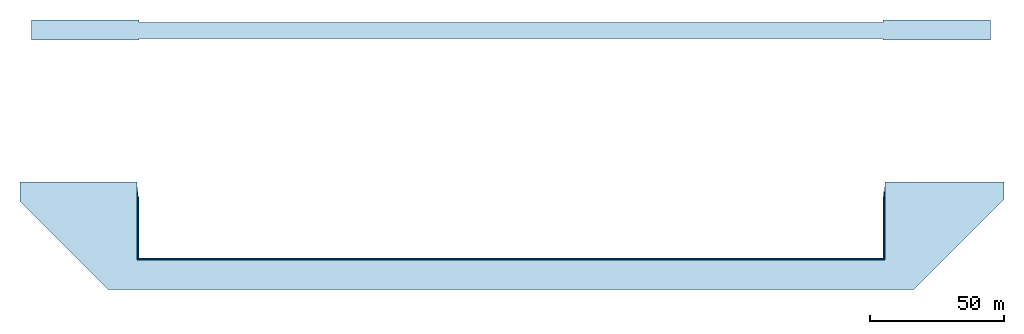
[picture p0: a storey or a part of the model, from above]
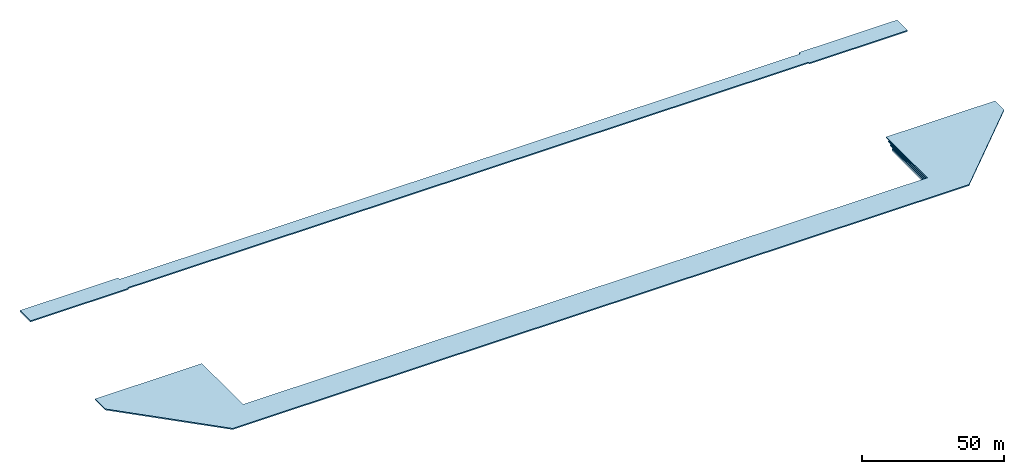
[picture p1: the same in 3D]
Properties of the parts of a building model (IFC2X3)

# File
Description: ViewDefinition [CoordinationView_V2.0]
Time: 2021-10-13T23:05:21
Written by: The EXPRESS Data Manager Version 5.02.0100.07 : 28 Aug 2013
Made in: 20210420_1515(x64) - Exporter 20.2.40.65 - 代替 UI 20.2.40.65
Comment: STEP Physical File produced by: The EXPRESS Data Manager Version 5.02.0100.07 : 28 Aug 2013 * Module: EDMstepFileFactory/EDMstandAlone * Creation date: Wed Oct 13 23:05:21 2021 * Host: A7687-TADA8 * Database: C:\Users\a9056\AppData\Local\Temp\cd053f27-3a5d-4f9c-bb79-c97ac7f12df1\53492a80-ce37-4b92-be3e-2d8bfc265d27\ifc * Database version: 5507 * Database creation date: Wed Oct 13 23:05:14 2021 * Schema: IFC2X3 * Model: DataRepository.ifc * Model creation date: Wed Oct 13 23:05:15 2021 * Header model: DataRepository.ifc_HeaderModel * Header model creation date: Wed Oct 13 23:05:15 2021 * EDMuser: sdai-user * EDMgroup: sdai-group * License ID and type: 5605 : Permanent license. Expiry date: * EDMstepFileFactory options: 020000

# IfcSite, Default
RefLatitude: 35, 53, 9, 550781; RefLongitude: 140, 22, 58, 619384; RefElevation: 0 mm

# IfcBuilding
Pset_BuildingCommon - NumberOfStoreys: 3

# IfcBuildingStorey: レベル:レベル 上表示 (3)
Name | LongName | Elevation (mm)
矢板 | 矢板 | 0
AP+8.200 | AP+8.200 | 8200
AP+10.800 | AP+10.800 | 10800

# IfcBuildingElementProxy: 鋼矢板10H型 (796)
In: 矢板
Type - Pset_BuildingElementProxyCommon - Reference: 鋼矢板10H型
Type - Pset_QuantityTakeOff - Reference: 鋼矢板10H型
Pset_BuildingElementProxyCommon - sets with these values: 2
Name (鋼矢板10H型:鋼矢板10H型:...)
734945
735249
735363
735376
735379
735382
735385
735388
735391
735394
735397
735400
735403
735406
735409
735412
735415
735418
735421
735424
735427
735430
735433
735436
735439
735442
735445
735448
735451
735454
735457
735460
735463
735466
735469
735472
735475
735478
735481
735484
735487
735490
735493
735496
735499
735502
735505
735508
735511
735514
735517
735520
735523
735526
735529
735532
735535
735538
735541
735544
735547
735550
735553
735556
735559
735562
735565
735568
735571
735574
735577
735580
735583
735586
735589
735592
735595
735598
735601
735604
735607
735610
735613
735616
735619
735622
735625
735628
735631
735634
735637
736566
736910
736923
736926
736929
736932
736935
736938
736941
736944
736947
736950
736953
736956
736959
736962
736965
736968
736971
736974
736977
736980
736983
736986
736989
736992
736995
736998
737001
737004
737007
737010
737013
737016
737019
737022
737025
737028
737031
737034
737037
737040
737043
737046
737049
737052
737055
737058
737061
737064
737067
737070
737073
737076
737079
737082
737085
737088
737091
737094
737097
737100
737103
737106
737109
737112
737115
737118
737121
737124
737127
737130
737133
737136
737139
737142
737145
737148
737151
737154
737157
737160
737163
737166
737169
737172
737175
737178
737181
737184
737187
737190
737193
737196
737199
737202
737205
737208
737211
737214
737217
737220
737223
737226
737229
737232
737235
737238
737241
737244
737247
737250
737253
737256
737259
737262
737265
737268
737271
737274
737277
737280
737283
737286
737289
737292
737295
737298
737301
737304
737307
737310
737313
737316
737319
737322
737325
737328
737331
737334
737337
737340
737343
737346
737349
737352
737355
737358
737361
737364
737367
737370
737373
737376
737379
737382
737385
737388
737391
737394
737397
737400
737403
737406
737409
737412
737415
737418
737421
737424
737427
737430
737433
737436
737439
737442
737445
737448
737451
737454
737457
737460
737463
737466
737469
737472
737475
737478
737481
737484
737487
737490
737493
737496
737499
737502
737505
737508
737511
737514
737517
737530
737533
737536
737539
737542
737545
737548
737551
737554
737557
737560
737563
737566
737569
737572
737575
737578
737581
737584
737587
737590
737593
737596
737599
737602
737605
737608
737611
737614
737617
737620
737623
737626
737629
737632
737635
737638
737641
737644
737647
737650
737653
737656
737659
737662
737665
737668
737671
737674
737677
737680
737683
737686
737689
737692
737695
737698
737701
737704
737707
737710
737713
737716
737719
737722
737725
737728
737731
737734
737737
737740
737743
737746
737749
737752
737755
737758
737761
737764
737767
737770
737773
737776
737779
737782
737785
737788
737791
737794
737797
737800
737803
737806
737809
737812
737815
737818
737821
737824
737827
737830
737833
737836
737839
737842
737899
737978
738010
738055
738068
738071
738074
738077
738080
738083
738086
738089
738092
738095
738098
738101
738104
738107
738110
738113
738116
738119
738122
738125
738128
738131
738134
738137
738140
738143
738146
738149
738152
738155
738158
738161
738164
738167
738170
738173
738176
738179
738182
738185
738188
738191
738194
738197
738200
738203
738206
738209
738212
738215
738218
738221
738224
738227
738230
738233
738236
738239
738242
738245
738248
738251
738254
738257
738260
738263
738266
738269
738272
738275
738278
738281
738284
738287
738290
738293
738296
738299
738302
738305
738308
738311
738314
738317
738320
738323
738326
738329
738342
738353
738356
738359
738362
738365
738368
738371
738374
738377
738380
738383
738386
738389
738392
738395
738398
738401
738404
738407
738410
738413
738416
738419
738422
738425
738428
738431
738434
738437
738440
738443
738446
738449
738452
738455
738458
738461
738464
738467
738470
738473
738476
738479
738482
738485
738488
738491
738494
738497
738500
738503
738506
738509
738512
738515
738518
738521
738524
738527
738530
738533
738536
738539
738542
738545
738548
738551
738554
738557
738560
738563
738566
738569
738572
738575
738578
738581
738584
738587
738590
738593
738596
738599
738602
738605
738608
738611
738614
738617
738620
738623
738626
738629
738632
738635
738638
738641
738644
738647
738650
738653
738656
738659
738662
738665
738668
738671
738674
738677
738680
738683
738686
738689
738692
738695
738698
738701
738704
738707
738710
738713
738716
738719
738722
738725
738728
738731
738734
738737
738740
738743
738746
738749
738752
738755
738758
738761
738764
738767
738770
738773
738776
738779
738782
738785
738788
738791
738794
738797
738800
738803
738806
738809
738812
738815
738818
738821
738824
738827
738830
738833
738836
738839
738842
738845
738848
738851
738854
738857
738860
738863
738866
738869
738872
738875
738878
738881
738884
738887
738890
738893
738896
738899
738902
738905
738908
738911
738914
738917
738920
738923
738926
738929
738932
738935
738938
738941
738944
738947
738958
738961
738964
738967
738970
738973
738976
738979
738982
738985
738988
738991
738994
738997
739000
739003
739006
739009
739012
739015
739018
739021
739024
739027
739030
739033
739036
739039
739042
739045
739048
739051
739054
739057
739060
739063
739066
739069
739072
739075
739078
739081
739084
739087
739090
739093
739096
739099
739102
739105
739108
739111
739114
739117
739120
739123
739126
739129
739132
739135
739138
739141
739144
739147
739150
739153
739156
739159
739162
739165
739168
739171
739174
739177
739180
739183
739186
739189
739192
739195
739198
739201
739204
739207
739210
739213
739216
739219
739222
739225
739228
739231
739234
739237
739240
739243
739246
739249
739252
739255
739258
739261
739264
739267
739270
739273
739276

# IfcSlab: かごマット, かごマット:かごマット:775933
In: AP+8.200
Type - PredefinedType: FLOOR
Type - Pset_QuantityTakeOff - Reference: かごマット
Type - Pset_ReinforcementBarPitchOfSlab - Reference: かごマット
Type - Pset_SlabCommon - IsExternal: no; Reference: かごマット
Pset_QuantityTakeOff - sets with these values: 2
Pset_SlabCommon - PitchAngle: 0 deg

# IfcSlab: アスファルト, アスファルト:アスファルト:769145
In: AP+10.800
Type - PredefinedType: FLOOR
Type - Pset_QuantityTakeOff - Reference: アスファルト
Type - Pset_ReinforcementBarPitchOfSlab - Reference: アスファルト
Type - Pset_SlabCommon - IsExternal: no; Reference: アスファルト
Pset_QuantityTakeOff - sets with these values: 2
Pset_SlabCommon - PitchAngle: 0 deg

# IfcSlab: トランジション, トランジション:トランジション:752253
In: 矢板
Type - PredefinedType: FLOOR
Type - Pset_QuantityTakeOff - Reference: トランジション
Type - Pset_ReinforcementBarPitchOfSlab - Reference: トランジション
Type - Pset_SlabCommon - IsExternal: no; Reference: トランジション
Pset_QuantityTakeOff - sets with these values: 2
Pset_SlabCommon - PitchAngle: 0 deg

# IfcSlab: 大型連節ブロック (2)
In: 矢板
Type - PredefinedType: FLOOR
Type - Pset_QuantityTakeOff - Reference: 大型連節ブロック
Type - Pset_ReinforcementBarPitchOfSlab - Reference: 大型連節ブロック
Type - Pset_SlabCommon - IsExternal: no; Reference: 大型連節ブロック
Pset_QuantityTakeOff - sets with these values: 2
Pset_SlabCommon - PitchAngle: 0 deg
Name
大型連節ブロック1:大型連節ブロック:785571
大型連節ブロック2:大型連節ブロック:785743

# IfcSlab: 笠コンクリート, 笠コンクリート:笠コンクリート:747056
In: 矢板
Type - PredefinedType: FLOOR
Type - Pset_QuantityTakeOff - Reference: 笠コンクリート
Type - Pset_ReinforcementBarPitchOfSlab - Reference: 笠コンクリート
Type - Pset_SlabCommon - Reference: 笠コンクリート; IsExternal: no
Pset_QuantityTakeOff - sets with these values: 2
Pset_SlabCommon - PitchAngle: 0 deg
